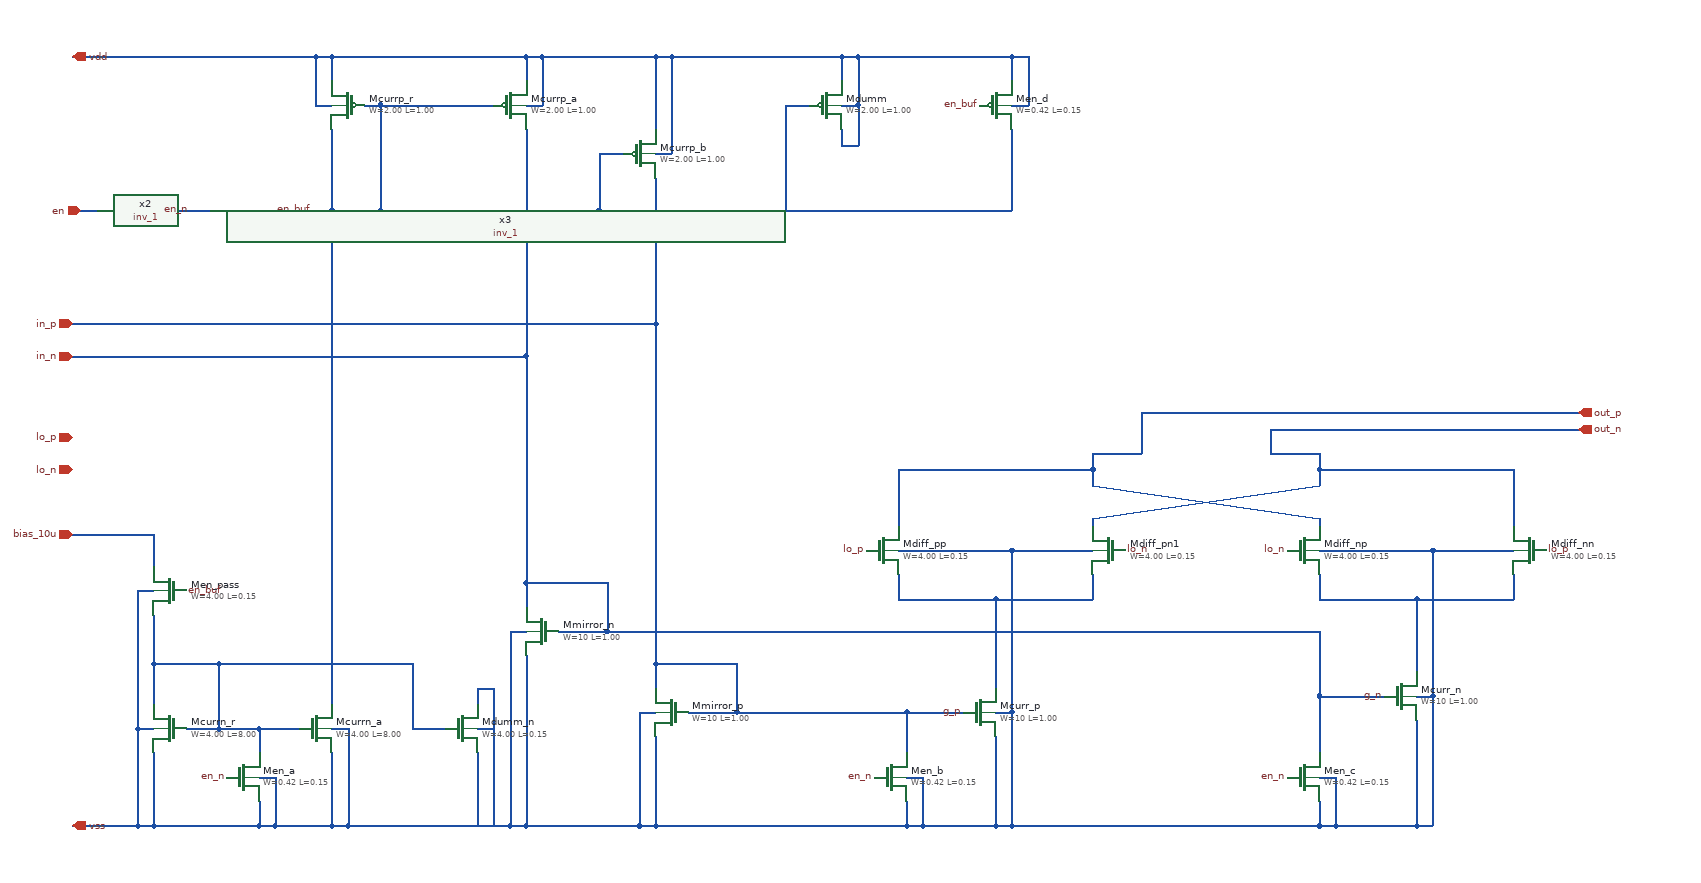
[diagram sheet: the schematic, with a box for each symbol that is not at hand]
v {xschem version=2.9.9 file_version=1.2 }
G {}
K {}
V {}
S {}
E {}
N 1020 -310 1020 -280 { lab=#net1}
N 1140 -280 1260 -280 { lab=#net1}
N 1260 -310 1260 -280 { lab=#net1}
N 1140 -280 1140 -170 { lab=#net1}
N 1160 -340 1260 -340 { lab=vss}
N 1160 -140 1160 0 { lab=vss}
N 1140 -110 1140 0 { lab=vss}
N 1140 -140 1160 -140 { lab=vss}
N 1540 -310 1540 -280 { lab=#net2}
N 1660 -280 1780 -280 { lab=#net2}
N 1780 -310 1780 -280 { lab=#net2}
N 1660 -280 1660 -190 { lab=#net2}
N 1680 -340 1780 -340 { lab=vss}
N 1680 -160 1680 0 { lab=vss}
N 1660 -130 1660 0 { lab=vss}
N 1660 -160 1680 -160 { lab=vss}
N 1030 -140 1100 -140 { lab=g_p}
N 700 -140 720 -140 { lab=vss}
N 700 -140 700 0 { lab=vss}
N 720 -110 720 0 { lab=vss}
N 720 -200 720 -170 { lab=g_p}
N 720 -200 820 -200 { lab=g_p}
N 820 -200 820 -140 { lab=g_p}
N 660 -240 1540 -240 { lab=g_n}
N 1540 -240 1540 -160 { lab=g_n}
N 1540 -160 1620 -160 { lab=g_n}
N 560 -300 560 -270 { lab=g_n}
N 560 -300 660 -300 { lab=g_n}
N 660 -300 660 -240 { lab=g_n}
N 560 -210 560 0 { lab=vss}
N 540 -240 560 -240 { lab=vss}
N 540 -240 540 0 { lab=vss}
N 1660 0 1680 0 { lab=vss}
N 1780 -440 1780 -370 { lab=out_n}
N 1020 -440 1020 -370 { lab=out_p}
N 1540 -440 1540 -420 { lab=out_n}
N 1260 -440 1260 -420 { lab=out_p}
N 1020 -280 1140 -280 { lab=#net1}
N 1020 -340 1160 -340 { lab=vss}
N 1140 0 1160 0 { lab=vss}
N 1050 0 1140 0 { lab=vss}
N 1160 -340 1160 -140 { lab=vss}
N 1540 -280 1660 -280 { lab=#net2}
N 1540 -340 1680 -340 { lab=vss}
N 1560 0 1660 0 { lab=vss}
N 1680 -340 1680 -160 { lab=vss}
N 560 0 700 0 { lab=vss}
N 700 0 720 0 { lab=vss}
N 760 -140 820 -140 { lab=g_p}
N 600 -240 660 -240 { lab=g_n}
N 540 0 560 0 { lab=vss}
N 1540 -440 1780 -440 { lab=out_n}
N 1020 -440 1260 -440 { lab=out_p}
N 1480 -490 1480 -460 { lab=out_n}
N 1480 -460 1540 -460 { lab=out_n}
N 1540 -460 1540 -440 { lab=out_n}
N 1320 -510 1320 -460 { lab=out_p}
N 1260 -460 1320 -460 { lab=out_p}
N 1260 -460 1260 -440 { lab=out_p}
N 580 -950 720 -950 { lab=vdd}
N 320 -950 560 -950 { lab=vdd}
N 720 -620 720 -200 { lab=g_p}
N 720 -830 740 -830 { lab=vdd}
N 740 -950 740 -830 { lab=vdd}
N 720 -950 720 -860 { lab=vdd}
N 560 -890 580 -890 { lab=vdd}
N 580 -950 580 -890 { lab=vdd}
N 560 -950 560 -920 { lab=vdd}
N 320 -860 320 -760 { lab=#net3}
N 380 -890 520 -890 { lab=#net3}
N 320 -950 320 -920 { lab=vdd}
N 380 -890 380 -760 { lab=#net3}
N 720 -950 740 -950 { lab=vdd}
N 560 -950 580 -950 { lab=vdd}
N 300 -950 320 -950 { lab=vdd}
N 360 -890 380 -890 { lab=#net3}
N 560 -580 560 -300 { lab=g_n}
N 320 -760 320 -150 { lab=#net3}
N 80 -120 100 -120 { lab=vss}
N 80 -120 80 0 { lab=vss}
N 340 0 540 0 { lab=vss}
N 320 -90 320 0 { lab=vss}
N 320 -120 340 -120 { lab=vss}
N 340 -120 340 0 { lab=vss}
N 100 -90 100 0 { lab=vss}
N 230 -120 280 -120 { lab=#net4}
N 100 -200 100 -150 { lab=#net4}
N 0 -580 560 -580 { lab=in_n}
N 0 -620 720 -620 { lab=in_p}
N 320 -760 380 -760 { lab=#net3}
N 380 -760 650 -760 { lab=#net3}
N 650 -830 650 -760 { lab=#net3}
N 650 -830 680 -830 { lab=#net3}
N 1540 -380 1540 -370 { lab=out_p}
N 1260 -420 1540 -380 { lab=out_p}
N 1260 -380 1540 -420 { lab=out_n}
N 1480 -490 1860 -490 { lab=out_n}
N 1320 -510 1860 -510 { lab=out_p}
N 80 -290 100 -290 { lab=vss}
N 80 -290 80 -120 { lab=vss}
N 100 -260 100 -200 { lab=#net4}
N 0 -360 100 -360 { lab=bias_10u}
N 100 -360 100 -320 { lab=bias_10u}
N 100 -200 180 -200 { lab=#net4}
N 180 -200 180 -120 { lab=#net4}
N 230 -120 230 -90 { lab=#net4}
N 230 -30 230 0 { lab=vss}
N 230 -60 250 -60 { lab=vss}
N 250 -60 250 0 { lab=vss}
N 1030 -30 1030 0 { lab=vss}
N 1030 -60 1050 -60 { lab=vss}
N 1050 -60 1050 0 { lab=vss}
N 1540 -30 1540 0 { lab=vss}
N 1540 -60 1560 -60 { lab=vss}
N 1560 -60 1560 0 { lab=vss}
N 1030 -140 1030 -90 { lab=g_p}
N 1540 -160 1540 -90 { lab=g_n}
N 1160 -950 1160 -920 { lab=vdd}
N 1160 -890 1180 -890 { lab=vdd}
N 1180 -950 1180 -890 { lab=vdd}
N 1160 -860 1160 -760 { lab=#net3}
N -0 0 80 -0 { lab=vss}
N 0 -950 300 -950 { lab=vdd}
N 110 -760 170 -760 { lab=en_n}
N 10 -760 30 -760 { lab=en}
N 300 -890 320 -890 { lab=vdd}
N 300 -950 300 -890 { lab=vdd}
N 250 0 320 0 { lab=vss}
N 320 0 340 0 { lab=vss}
N 80 0 100 0 { lab=vss}
N 560 -860 560 -580 { lab=g_n}
N 720 -800 720 -620 { lab=g_p}
N 140 -120 180 -120 { lab=#net4}
N 180 -120 230 -120 { lab=#net4}
N 100 0 230 0 { lab=vss}
N 230 0 250 0 { lab=vss}
N 720 0 1030 0 { lab=vss}
N 1030 0 1050 0 { lab=vss}
N 1160 0 1540 0 { lab=vss}
N 1540 0 1560 0 { lab=vss}
N 820 -140 1030 -140 { lab=g_p}
N 970 -950 1160 -950 { lab=vdd}
N 1160 -950 1180 -950 { lab=vdd}
N 950 -760 1160 -760 { lab=#net3}
N 1260 -380 1260 -370 { lab=out_n}
N 950 -890 970 -890 { lab=vdd}
N 970 -950 970 -890 { lab=vdd}
N 950 -950 950 -920 { lab=vdd}
N 950 -950 970 -950 { lab=vdd}
N 880 -890 910 -890 { lab=#net3}
N 880 -890 880 -830 { lab=#net3}
N 420 -120 460 -120 {}
N 420 -200 420 -120 {}
N 180 -200 420 -200 {}
N 740 -950 950 -950 { lab=vdd}
N 650 -760 950 -760 { lab=#net3}
N 500 -170 500 -150 {}
N 500 -90 500 0 {}
N 500 -170 520 -170 {}
N 520 -170 520 0 {}
N 500 -120 520 -120 {}
N 950 -860 950 -840 {}
N 950 -840 970 -840 {}
N 970 -890 970 -840 {}
N 880 -830 880 -760 {}
C {sky130_fd_pr/nfet_01v8_lvt.sym} 1120 -140 0 0 {name=Mcurr_p
L=1.00
W=10
nf=2
mult=8
ad="'int((nf+1)/2) * W/nf * 0.29'" 
pd="'2*int((nf+1)/2) * (W/nf + 0.29)'"
as="'int((nf+2)/2) * W/nf * 0.29'" 
ps="'2*int((nf+2)/2) * (W/nf + 0.29)'"
nrd="'0.29 / W'" nrs="'0.29 / W'"
sa=0 sb=0 sd=0
model=nfet_01v8_lvt
spiceprefix=X
}
C {sky130_fd_pr/nfet_01v8_lvt.sym} 1000 -340 0 0 {name=Mdiff_pp
L=0.15
W=4.00
nf=1
mult=2
ad="'int((nf+1)/2) * W/nf * 0.29'" 
pd="'2*int((nf+1)/2) * (W/nf + 0.29)'"
as="'int((nf+2)/2) * W/nf * 0.29'" 
ps="'2*int((nf+2)/2) * (W/nf + 0.29)'"
nrd="'0.29 / W'" nrs="'0.29 / W'"
sa=0 sb=0 sd=0
model=nfet_01v8_lvt
spiceprefix=X
}
C {sky130_fd_pr/nfet_01v8_lvt.sym} 1280 -340 0 1 {name=Mdiff_pn1
L=0.15
W=4.00
nf=1
mult=2
ad="'int((nf+1)/2) * W/nf * 0.29'" 
pd="'2*int((nf+1)/2) * (W/nf + 0.29)'"
as="'int((nf+2)/2) * W/nf * 0.29'" 
ps="'2*int((nf+2)/2) * (W/nf + 0.29)'"
nrd="'0.29 / W'" nrs="'0.29 / W'"
sa=0 sb=0 sd=0
model=nfet_01v8_lvt
spiceprefix=X
}
C {sky130_fd_pr/nfet_01v8_lvt.sym} 1640 -160 0 0 {name=Mcurr_n
L=1.00
W=10
nf=2
mult=8
ad="'int((nf+1)/2) * W/nf * 0.29'" 
pd="'2*int((nf+1)/2) * (W/nf + 0.29)'"
as="'int((nf+2)/2) * W/nf * 0.29'" 
ps="'2*int((nf+2)/2) * (W/nf + 0.29)'"
nrd="'0.29 / W'" nrs="'0.29 / W'"
sa=0 sb=0 sd=0
model=nfet_01v8_lvt
spiceprefix=X
}
C {sky130_fd_pr/nfet_01v8_lvt.sym} 1520 -340 0 0 {name=Mdiff_np
L=0.15
W=4.00
nf=1
mult=2
ad="'int((nf+1)/2) * W/nf * 0.29'" 
pd="'2*int((nf+1)/2) * (W/nf + 0.29)'"
as="'int((nf+2)/2) * W/nf * 0.29'" 
ps="'2*int((nf+2)/2) * (W/nf + 0.29)'"
nrd="'0.29 / W'" nrs="'0.29 / W'"
sa=0 sb=0 sd=0
model=nfet_01v8_lvt
spiceprefix=X
}
C {sky130_fd_pr/nfet_01v8_lvt.sym} 1800 -340 0 1 {name=Mdiff_nn
L=0.15
W=4.00
nf=1
mult=2
ad="'int((nf+1)/2) * W/nf * 0.29'" 
pd="'2*int((nf+1)/2) * (W/nf + 0.29)'"
as="'int((nf+2)/2) * W/nf * 0.29'" 
ps="'2*int((nf+2)/2) * (W/nf + 0.29)'"
nrd="'0.29 / W'" nrs="'0.29 / W'"
sa=0 sb=0 sd=0
model=nfet_01v8_lvt
spiceprefix=X
}
C {sky130_fd_pr/nfet_01v8_lvt.sym} 580 -240 0 1 {name=Mmirror_n
L=1.00
W=10
nf=2
mult=2
ad="'int((nf+1)/2) * W/nf * 0.29'" 
pd="'2*int((nf+1)/2) * (W/nf + 0.29)'"
as="'int((nf+2)/2) * W/nf * 0.29'" 
ps="'2*int((nf+2)/2) * (W/nf + 0.29)'"
nrd="'0.29 / W'" nrs="'0.29 / W'"
sa=0 sb=0 sd=0
model=nfet_01v8_lvt
spiceprefix=X
}
C {sky130_fd_pr/nfet_01v8_lvt.sym} 740 -140 0 1 {name=Mmirror_p
L=1.00
W=10
nf=2
mult=2
ad="'int((nf+1)/2) * W/nf * 0.29'" 
pd="'2*int((nf+1)/2) * (W/nf + 0.29)'"
as="'int((nf+2)/2) * W/nf * 0.29'" 
ps="'2*int((nf+2)/2) * (W/nf + 0.29)'"
nrd="'0.29 / W'" nrs="'0.29 / W'"
sa=0 sb=0 sd=0
model=nfet_01v8_lvt
spiceprefix=X
}
C {lab_wire.sym} 1100 -140 0 0 {name=l11 sig_type=std_logic lab=g_p}
C {lab_wire.sym} 1620 -160 0 0 {name=l10 sig_type=std_logic lab=g_n}
C {lab_wire.sym} 1300 -340 0 1 {name=l1 sig_type=std_logic lab=lo_n}
C {lab_wire.sym} 1500 -340 0 0 {name=l3 sig_type=std_logic lab=lo_n}
C {lab_wire.sym} 1820 -340 0 1 {name=l4 sig_type=std_logic lab=lo_p}
C {lab_wire.sym} 980 -340 0 0 {name=l2 sig_type=std_logic lab=lo_p}
C {sky130_fd_pr/nfet_01v8_lvt.sym} 120 -120 0 1 {name=Mcurrn_r
L=8.00
W=4.00
nf=1
mult=2
ad="'int((nf+1)/2) * W/nf * 0.29'" 
pd="'2*int((nf+1)/2) * (W/nf + 0.29)'"
as="'int((nf+2)/2) * W/nf * 0.29'" 
ps="'2*int((nf+2)/2) * (W/nf + 0.29)'"
nrd="'0.29 / W'" nrs="'0.29 / W'"
sa=0 sb=0 sd=0
model=nfet_01v8_lvt
spiceprefix=X
}
C {sky130_fd_pr/nfet_01v8_lvt.sym} 300 -120 0 0 {name=Mcurrn_a
L=8.00
W=4.00
nf=1
mult=2
ad="'int((nf+1)/2) * W/nf * 0.29'" 
pd="'2*int((nf+1)/2) * (W/nf + 0.29)'"
as="'int((nf+2)/2) * W/nf * 0.29'" 
ps="'2*int((nf+2)/2) * (W/nf + 0.29)'"
nrd="'0.29 / W'" nrs="'0.29 / W'"
sa=0 sb=0 sd=0
model=nfet_01v8_lvt
spiceprefix=X
}
C {ipin.sym} 0 -580 0 0 {name=p1 lab=in_n}
C {ipin.sym} 0 -620 0 0 {name=p2 lab=in_p}
C {sky130_fd_pr/pfet_01v8_lvt.sym} 340 -890 0 1 {name=Mcurrp_r
L=1.00
W=2.00
nf=1
mult=1
ad="'int((nf+1)/2) * W/nf * 0.29'" 
pd="'2*int((nf+1)/2) * (W/nf + 0.29)'"
as="'int((nf+2)/2) * W/nf * 0.29'" 
ps="'2*int((nf+2)/2) * (W/nf + 0.29)'"
nrd="'0.29 / W'" nrs="'0.29 / W'"
sa=0 sb=0 sd=0
model=pfet_01v8_lvt
spiceprefix=X
}
C {sky130_fd_pr/pfet_01v8_lvt.sym} 540 -890 0 0 {name=Mcurrp_a
L=1.00
W=2.00
nf=1
mult=10
ad="'int((nf+1)/2) * W/nf * 0.29'" 
pd="'2*int((nf+1)/2) * (W/nf + 0.29)'"
as="'int((nf+2)/2) * W/nf * 0.29'" 
ps="'2*int((nf+2)/2) * (W/nf + 0.29)'"
nrd="'0.29 / W'" nrs="'0.29 / W'"
sa=0 sb=0 sd=0
model=pfet_01v8_lvt
spiceprefix=X
}
C {sky130_fd_pr/pfet_01v8_lvt.sym} 700 -830 0 0 {name=Mcurrp_b
L=1.00
W=2.00
nf=1
mult=10
ad="'int((nf+1)/2) * W/nf * 0.29'" 
pd="'2*int((nf+1)/2) * (W/nf + 0.29)'"
as="'int((nf+2)/2) * W/nf * 0.29'" 
ps="'2*int((nf+2)/2) * (W/nf + 0.29)'"
nrd="'0.29 / W'" nrs="'0.29 / W'"
sa=0 sb=0 sd=0
model=pfet_01v8_lvt
spiceprefix=X
}
C {ipin.sym} 0 -360 0 0 {name=p3 lab=bias_10u}
C {sky130_fd_pr/nfet_01v8.sym} 210 -60 0 0 {name=Men_a
L=0.15
W=0.42
nf=1 
mult=1
ad="'int((nf+1)/2) * W/nf * 0.29'" 
pd="'2*int((nf+1)/2) * (W/nf + 0.29)'"
as="'int((nf+2)/2) * W/nf * 0.29'" 
ps="'2*int((nf+2)/2) * (W/nf + 0.29)'"
nrd="'0.29 / W'" nrs="'0.29 / W'"
sa=0 sb=0 sd=0
model=nfet_01v8
spiceprefix=X
}
C {sky130_fd_pr/nfet_01v8_lvt.sym} 120 -290 0 1 {name=Men_pass
L=0.15
W=4.00
nf=1
mult=2
ad="'int((nf+1)/2) * W/nf * 0.29'" 
pd="'2*int((nf+1)/2) * (W/nf + 0.29)'"
as="'int((nf+2)/2) * W/nf * 0.29'" 
ps="'2*int((nf+2)/2) * (W/nf + 0.29)'"
nrd="'0.29 / W'" nrs="'0.29 / W'"
sa=0 sb=0 sd=0
model=nfet_01v8_lvt
spiceprefix=X
}
C {lab_pin.sym} 140 -290 0 1 {name=l7 sig_type=std_logic lab=en_buf}
C {lab_pin.sym} 190 -60 0 0 {name=l6 sig_type=std_logic lab=en_n}
C {sky130_fd_pr/nfet_01v8.sym} 1010 -60 0 0 {name=Men_b
L=0.15
W=0.42
nf=1 
mult=1
ad="'int((nf+1)/2) * W/nf * 0.29'" 
pd="'2*int((nf+1)/2) * (W/nf + 0.29)'"
as="'int((nf+2)/2) * W/nf * 0.29'" 
ps="'2*int((nf+2)/2) * (W/nf + 0.29)'"
nrd="'0.29 / W'" nrs="'0.29 / W'"
sa=0 sb=0 sd=0
model=nfet_01v8
spiceprefix=X
}
C {lab_pin.sym} 990 -60 0 0 {name=l8 sig_type=std_logic lab=en_n}
C {sky130_fd_pr/nfet_01v8.sym} 1520 -60 0 0 {name=Men_c
L=0.15
W=0.42
nf=1 
mult=1
ad="'int((nf+1)/2) * W/nf * 0.29'" 
pd="'2*int((nf+1)/2) * (W/nf + 0.29)'"
as="'int((nf+2)/2) * W/nf * 0.29'" 
ps="'2*int((nf+2)/2) * (W/nf + 0.29)'"
nrd="'0.29 / W'" nrs="'0.29 / W'"
sa=0 sb=0 sd=0
model=nfet_01v8
spiceprefix=X
}
C {lab_pin.sym} 1500 -60 0 0 {name=l9 sig_type=std_logic lab=en_n}
C {sky130_fd_pr/pfet_01v8.sym} 1140 -890 0 0 {name=Men_d
L=0.15
W=0.42
nf=1
mult=1
ad="'int((nf+1)/2) * W/nf * 0.29'" 
pd="'2*int((nf+1)/2) * (W/nf + 0.29)'"
as="'int((nf+2)/2) * W/nf * 0.29'" 
ps="'2*int((nf+2)/2) * (W/nf + 0.29)'"
nrd="'0.29 / W'" nrs="'0.29 / W'"
sa=0 sb=0 sd=0
model=pfet_01v8
spiceprefix=X
}
C {lab_pin.sym} 1120 -890 0 0 {name=l12 sig_type=std_logic lab=en_buf}
C {iopin.sym} 0 0 0 1 {name=p4 lab=vss}
C {iopin.sym} 0 -950 0 1 {name=p5 lab=vdd}
C {opin.sym} 1860 -510 0 0 {name=p6 lab=out_p}
C {opin.sym} 1860 -490 0 0 {name=p7 lab=out_n}
C {sky130_stdcells/inv_1.sym} 70 -760 0 0 {name=x2 VGND=vss VNB=vss VPB=vdd VPWR=vdd prefix=sky130_fd_sc_hs__ }
C {lab_wire.sym} 110 -760 0 1 {name=l13 sig_type=std_logic lab=en_n}
C {lab_wire.sym} 250 -760 0 1 {name=l14 sig_type=std_logic lab=en_buf}
C {ipin.sym} 10 -760 0 0 {name=p8 lab=en}
C {sky130_stdcells/inv_1.sym} 210 -760 0 0 {name=x3 VGND=vss VNB=vss VPB=vdd VPWR=vdd prefix=sky130_fd_sc_hs__ }
C {ipin.sym} 0 -440 0 0 {name=p9 lab=lo_n}
C {ipin.sym} 0 -480 0 0 {name=p10 lab=lo_p}
C {sky130_fd_pr/pfet_01v8_lvt.sym} 930 -890 0 0 {name=Mdumm
L=1.00
W=2.00
nf=1
mult=4
ad="'int((nf+1)/2) * W/nf * 0.29'" 
pd="'2*int((nf+1)/2) * (W/nf + 0.29)'"
as="'int((nf+2)/2) * W/nf * 0.29'" 
ps="'2*int((nf+2)/2) * (W/nf + 0.29)'"
nrd="'0.29 / W'" nrs="'0.29 / W'"
sa=0 sb=0 sd=0
model=pfet_01v8_lvt
spiceprefix=X
}
C {sky130_fd_pr/nfet_01v8_lvt.sym} 480 -120 0 0 {name=Mdumm_n
L=0.15
W=4.00
nf=1
mult=2
ad="'int((nf+1)/2) * W/nf * 0.29'" 
pd="'2*int((nf+1)/2) * (W/nf + 0.29)'"
as="'int((nf+2)/2) * W/nf * 0.29'" 
ps="'2*int((nf+2)/2) * (W/nf + 0.29)'"
nrd="'0.29 / W'" nrs="'0.29 / W'"
sa=0 sb=0 sd=0
model=nfet_01v8_lvt
spiceprefix=X
}
